VERSION 5.7 ;
  NOWIREEXTENSIONATPIN ON ;
  DIVIDERCHAR "/" ;
  BUSBITCHARS "[]" ;
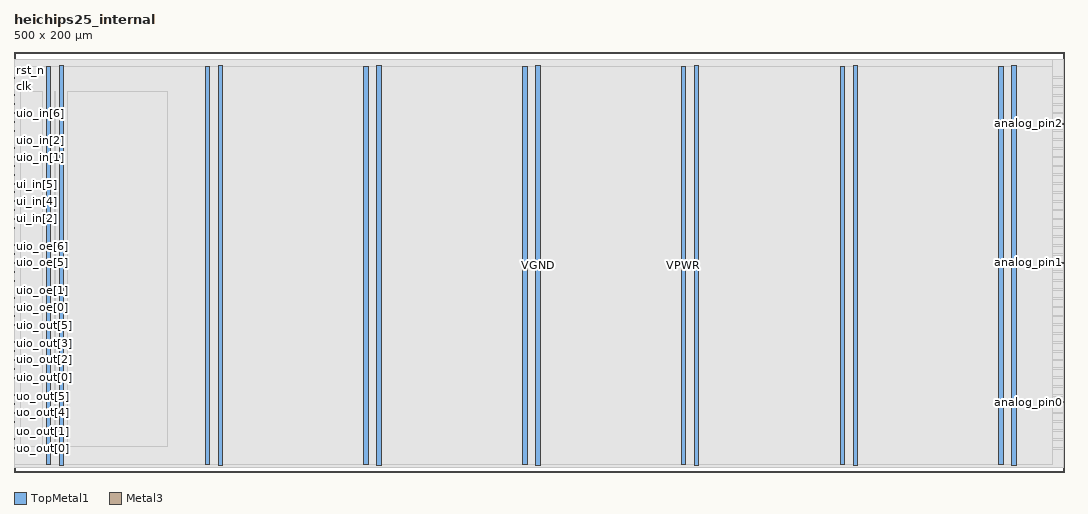
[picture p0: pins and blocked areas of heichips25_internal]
MACRO heichips25_internal
  CLASS BLOCK ;
  FOREIGN heichips25_internal ;
  ORIGIN 0.000 0.000 ;
  SIZE 500.000 BY 200.000 ;
  PIN VGND
    DIRECTION INOUT ;
    USE GROUND ;
    PORT
      LAYER TopMetal1 ;
        RECT 21.580 3.150 23.780 193.410 ;
    END
    PORT
      LAYER TopMetal1 ;
        RECT 97.180 3.150 99.380 193.410 ;
    END
    PORT
      LAYER TopMetal1 ;
        RECT 172.780 3.150 174.980 193.410 ;
    END
    PORT
      LAYER TopMetal1 ;
        RECT 248.380 3.150 250.580 193.410 ;
    END
    PORT
      LAYER TopMetal1 ;
        RECT 323.980 3.150 326.180 193.410 ;
    END
    PORT
      LAYER TopMetal1 ;
        RECT 399.580 3.150 401.780 193.410 ;
    END
    PORT
      LAYER TopMetal1 ;
        RECT 475.180 3.150 477.380 193.410 ;
    END
  END VGND
  PIN VPWR
    DIRECTION INOUT ;
    USE POWER ;
    PORT
      LAYER TopMetal1 ;
        RECT 15.380 3.560 17.580 193.000 ;
    END
    PORT
      LAYER TopMetal1 ;
        RECT 90.980 3.560 93.180 193.000 ;
    END
    PORT
      LAYER TopMetal1 ;
        RECT 166.580 3.560 168.780 193.000 ;
    END
    PORT
      LAYER TopMetal1 ;
        RECT 242.180 3.560 244.380 193.000 ;
    END
    PORT
      LAYER TopMetal1 ;
        RECT 317.780 3.560 319.980 193.000 ;
    END
    PORT
      LAYER TopMetal1 ;
        RECT 393.380 3.560 395.580 193.000 ;
    END
    PORT
      LAYER TopMetal1 ;
        RECT 468.980 3.560 471.180 193.000 ;
    END
  END VPWR
  PIN analog_pin0
    DIRECTION INOUT ;
    USE SIGNAL ;
    ANTENNADIFFAREA 5.654400 ;
    PORT
      LAYER Metal3 ;
        RECT 490.660 32.980 500.000 33.380 ;
    END
  END analog_pin0
  PIN analog_pin1
    DIRECTION INOUT ;
    USE SIGNAL ;
    ANTENNADIFFAREA 5.654400 ;
    PORT
      LAYER Metal3 ;
        RECT 494.980 99.340 500.000 99.740 ;
    END
  END analog_pin1
  PIN analog_pin2
    DIRECTION INOUT ;
    USE SIGNAL ;
    ANTENNADIFFAREA 5.654400 ;
    PORT
      LAYER Metal3 ;
        RECT 495.460 165.700 500.000 166.100 ;
    END
  END analog_pin2
  PIN clk
    DIRECTION INPUT ;
    USE SIGNAL ;
    ANTENNAGATEAREA 2.901600 ;
    PORT
      LAYER Metal3 ;
        RECT 0.000 183.340 0.400 183.740 ;
    END
  END clk
  PIN ena
    DIRECTION INPUT ;
    USE SIGNAL ;
    ANTENNAGATEAREA 0.180700 ;
    ANTENNADIFFAREA 2.015400 ;
    PORT
      LAYER Metal3 ;
        RECT 0.000 179.140 0.400 179.540 ;
    END
  END ena
  PIN rst_n
    DIRECTION INPUT ;
    USE SIGNAL ;
    ANTENNAGATEAREA 0.180700 ;
    PORT
      LAYER Metal3 ;
        RECT 0.000 187.540 0.400 187.940 ;
    END
  END rst_n
  PIN ui_in[0]
    DIRECTION INPUT ;
    USE SIGNAL ;
    ANTENNAGATEAREA 0.180700 ;
    PORT
      LAYER Metal3 ;
        RECT 0.000 111.940 0.400 112.340 ;
    END
  END ui_in[0]
  PIN ui_in[1]
    DIRECTION INPUT ;
    USE SIGNAL ;
    ANTENNAGATEAREA 0.180700 ;
    PORT
      LAYER Metal3 ;
        RECT 0.000 116.140 0.400 116.540 ;
    END
  END ui_in[1]
  PIN ui_in[2]
    DIRECTION INPUT ;
    USE SIGNAL ;
    ANTENNAGATEAREA 0.180700 ;
    PORT
      LAYER Metal3 ;
        RECT 0.000 120.340 0.400 120.740 ;
    END
  END ui_in[2]
  PIN ui_in[3]
    DIRECTION INPUT ;
    USE SIGNAL ;
    ANTENNAGATEAREA 0.180700 ;
    PORT
      LAYER Metal3 ;
        RECT 0.000 124.540 0.400 124.940 ;
    END
  END ui_in[3]
  PIN ui_in[4]
    DIRECTION INPUT ;
    USE SIGNAL ;
    ANTENNAGATEAREA 0.180700 ;
    PORT
      LAYER Metal3 ;
        RECT 0.000 128.740 0.400 129.140 ;
    END
  END ui_in[4]
  PIN ui_in[5]
    DIRECTION INPUT ;
    USE SIGNAL ;
    ANTENNAGATEAREA 0.180700 ;
    ANTENNADIFFAREA 2.015400 ;
    PORT
      LAYER Metal3 ;
        RECT 0.000 132.940 0.400 133.340 ;
    END
  END ui_in[5]
  PIN ui_in[6]
    DIRECTION INPUT ;
    USE SIGNAL ;
    ANTENNAGATEAREA 0.180700 ;
    PORT
      LAYER Metal3 ;
        RECT 0.000 137.140 0.400 137.540 ;
    END
  END ui_in[6]
  PIN ui_in[7]
    DIRECTION INPUT ;
    USE SIGNAL ;
    ANTENNAGATEAREA 0.180700 ;
    PORT
      LAYER Metal3 ;
        RECT 0.000 141.340 0.400 141.740 ;
    END
  END ui_in[7]
  PIN uio_in[0]
    DIRECTION INPUT ;
    USE SIGNAL ;
    ANTENNAGATEAREA 0.180700 ;
    ANTENNADIFFAREA 2.015400 ;
    PORT
      LAYER Metal3 ;
        RECT 0.000 145.540 0.400 145.940 ;
    END
  END uio_in[0]
  PIN uio_in[1]
    DIRECTION INPUT ;
    USE SIGNAL ;
    ANTENNAGATEAREA 0.180700 ;
    PORT
      LAYER Metal3 ;
        RECT 0.000 149.740 0.400 150.140 ;
    END
  END uio_in[1]
  PIN uio_in[2]
    DIRECTION INPUT ;
    USE SIGNAL ;
    ANTENNAGATEAREA 0.180700 ;
    PORT
      LAYER Metal3 ;
        RECT 0.000 153.940 0.400 154.340 ;
    END
  END uio_in[2]
  PIN uio_in[3]
    DIRECTION INPUT ;
    USE SIGNAL ;
    ANTENNAGATEAREA 0.180700 ;
    PORT
      LAYER Metal3 ;
        RECT 0.000 158.140 0.400 158.540 ;
    END
  END uio_in[3]
  PIN uio_in[4]
    DIRECTION INPUT ;
    USE SIGNAL ;
    PORT
      LAYER Metal3 ;
        RECT 0.000 162.340 0.400 162.740 ;
    END
  END uio_in[4]
  PIN uio_in[5]
    DIRECTION INPUT ;
    USE SIGNAL ;
    PORT
      LAYER Metal3 ;
        RECT 0.000 166.540 0.400 166.940 ;
    END
  END uio_in[5]
  PIN uio_in[6]
    DIRECTION INPUT ;
    USE SIGNAL ;
    PORT
      LAYER Metal3 ;
        RECT 0.000 170.740 0.400 171.140 ;
    END
  END uio_in[6]
  PIN uio_in[7]
    DIRECTION INPUT ;
    USE SIGNAL ;
    PORT
      LAYER Metal3 ;
        RECT 0.000 174.940 0.400 175.340 ;
    END
  END uio_in[7]
  PIN uio_oe[0]
    DIRECTION OUTPUT ;
    USE SIGNAL ;
    ANTENNADIFFAREA 0.708600 ;
    PORT
      LAYER Metal3 ;
        RECT 0.000 78.340 0.400 78.740 ;
    END
  END uio_oe[0]
  PIN uio_oe[1]
    DIRECTION OUTPUT ;
    USE SIGNAL ;
    ANTENNADIFFAREA 0.708600 ;
    PORT
      LAYER Metal3 ;
        RECT 0.000 82.540 0.400 82.940 ;
    END
  END uio_oe[1]
  PIN uio_oe[2]
    DIRECTION OUTPUT ;
    USE SIGNAL ;
    ANTENNADIFFAREA 0.708600 ;
    PORT
      LAYER Metal3 ;
        RECT 0.000 86.740 0.400 87.140 ;
    END
  END uio_oe[2]
  PIN uio_oe[3]
    DIRECTION OUTPUT ;
    USE SIGNAL ;
    ANTENNADIFFAREA 0.708600 ;
    PORT
      LAYER Metal3 ;
        RECT 0.000 90.940 0.400 91.340 ;
    END
  END uio_oe[3]
  PIN uio_oe[4]
    DIRECTION OUTPUT ;
    USE SIGNAL ;
    ANTENNADIFFAREA 0.708600 ;
    PORT
      LAYER Metal3 ;
        RECT 0.000 95.140 0.400 95.540 ;
    END
  END uio_oe[4]
  PIN uio_oe[5]
    DIRECTION OUTPUT ;
    USE SIGNAL ;
    ANTENNADIFFAREA 0.708600 ;
    PORT
      LAYER Metal3 ;
        RECT 0.000 99.340 0.400 99.740 ;
    END
  END uio_oe[5]
  PIN uio_oe[6]
    DIRECTION OUTPUT ;
    USE SIGNAL ;
    ANTENNADIFFAREA 0.708600 ;
    PORT
      LAYER Metal3 ;
        RECT 0.000 103.540 0.400 103.940 ;
    END
  END uio_oe[6]
  PIN uio_oe[7]
    DIRECTION OUTPUT ;
    USE SIGNAL ;
    ANTENNADIFFAREA 0.708600 ;
    PORT
      LAYER Metal3 ;
        RECT 0.000 107.740 0.400 108.140 ;
    END
  END uio_oe[7]
  PIN uio_out[0]
    DIRECTION OUTPUT ;
    USE SIGNAL ;
    ANTENNADIFFAREA 0.708600 ;
    PORT
      LAYER Metal3 ;
        RECT 0.000 44.740 0.400 45.140 ;
    END
  END uio_out[0]
  PIN uio_out[1]
    DIRECTION OUTPUT ;
    USE SIGNAL ;
    ANTENNADIFFAREA 0.708600 ;
    PORT
      LAYER Metal3 ;
        RECT 0.000 48.940 0.400 49.340 ;
    END
  END uio_out[1]
  PIN uio_out[2]
    DIRECTION OUTPUT ;
    USE SIGNAL ;
    ANTENNADIFFAREA 0.708600 ;
    PORT
      LAYER Metal3 ;
        RECT 0.000 53.140 0.400 53.540 ;
    END
  END uio_out[2]
  PIN uio_out[3]
    DIRECTION OUTPUT ;
    USE SIGNAL ;
    ANTENNADIFFAREA 0.708600 ;
    PORT
      LAYER Metal3 ;
        RECT 0.000 57.340 0.400 57.740 ;
    END
  END uio_out[3]
  PIN uio_out[4]
    DIRECTION OUTPUT ;
    USE SIGNAL ;
    ANTENNADIFFAREA 0.708600 ;
    PORT
      LAYER Metal3 ;
        RECT 0.000 61.540 0.400 61.940 ;
    END
  END uio_out[4]
  PIN uio_out[5]
    DIRECTION OUTPUT ;
    USE SIGNAL ;
    ANTENNADIFFAREA 0.708600 ;
    PORT
      LAYER Metal3 ;
        RECT 0.000 65.740 0.400 66.140 ;
    END
  END uio_out[5]
  PIN uio_out[6]
    DIRECTION OUTPUT ;
    USE SIGNAL ;
    ANTENNADIFFAREA 0.708600 ;
    PORT
      LAYER Metal3 ;
        RECT 0.000 69.940 0.400 70.340 ;
    END
  END uio_out[6]
  PIN uio_out[7]
    DIRECTION OUTPUT ;
    USE SIGNAL ;
    ANTENNADIFFAREA 0.708600 ;
    PORT
      LAYER Metal3 ;
        RECT 0.000 74.140 0.400 74.540 ;
    END
  END uio_out[7]
  PIN uo_out[0]
    DIRECTION OUTPUT ;
    USE SIGNAL ;
    ANTENNADIFFAREA 0.708600 ;
    PORT
      LAYER Metal3 ;
        RECT 0.000 11.140 0.400 11.540 ;
    END
  END uo_out[0]
  PIN uo_out[1]
    DIRECTION OUTPUT ;
    USE SIGNAL ;
    ANTENNADIFFAREA 0.708600 ;
    PORT
      LAYER Metal3 ;
        RECT 0.000 15.340 0.400 15.740 ;
    END
  END uo_out[1]
  PIN uo_out[2]
    DIRECTION OUTPUT ;
    USE SIGNAL ;
    ANTENNADIFFAREA 0.708600 ;
    PORT
      LAYER Metal3 ;
        RECT 0.000 19.540 0.400 19.940 ;
    END
  END uo_out[2]
  PIN uo_out[3]
    DIRECTION OUTPUT ;
    USE SIGNAL ;
    ANTENNADIFFAREA 0.708600 ;
    PORT
      LAYER Metal3 ;
        RECT 0.000 23.740 0.400 24.140 ;
    END
  END uo_out[3]
  PIN uo_out[4]
    DIRECTION OUTPUT ;
    USE SIGNAL ;
    ANTENNADIFFAREA 0.708600 ;
    PORT
      LAYER Metal3 ;
        RECT 0.000 27.940 0.400 28.340 ;
    END
  END uo_out[4]
  PIN uo_out[5]
    DIRECTION OUTPUT ;
    USE SIGNAL ;
    ANTENNADIFFAREA 0.708600 ;
    PORT
      LAYER Metal3 ;
        RECT 0.000 32.140 0.400 32.540 ;
    END
  END uo_out[5]
  PIN uo_out[6]
    DIRECTION OUTPUT ;
    USE SIGNAL ;
    ANTENNADIFFAREA 0.708600 ;
    PORT
      LAYER Metal3 ;
        RECT 0.000 36.340 0.400 36.740 ;
    END
  END uo_out[6]
  PIN uo_out[7]
    DIRECTION OUTPUT ;
    USE SIGNAL ;
    ANTENNADIFFAREA 0.708600 ;
    PORT
      LAYER Metal3 ;
        RECT 0.000 40.540 0.400 40.940 ;
    END
  END uo_out[7]
  OBS
      LAYER GatPoly ;
        RECT 2.880 3.630 496.800 192.930 ;
      LAYER Metal1 ;
        RECT 2.880 3.560 496.800 193.000 ;
      LAYER Metal2 ;
        RECT 0.375 1.955 495.660 196.285 ;
      LAYER Metal3 ;
        RECT 0.100 188.150 499.800 196.245 ;
        RECT 0.610 187.330 499.800 188.150 ;
        RECT 0.100 183.950 499.800 187.330 ;
        RECT 0.610 183.130 499.800 183.950 ;
        RECT 0.100 179.750 499.800 183.130 ;
        RECT 0.610 178.930 499.800 179.750 ;
        RECT 0.100 175.550 499.800 178.930 ;
        RECT 0.610 174.730 499.800 175.550 ;
        RECT 0.100 171.350 499.800 174.730 ;
        RECT 0.610 170.530 499.800 171.350 ;
        RECT 0.100 167.150 499.800 170.530 ;
        RECT 0.610 166.330 499.800 167.150 ;
        RECT 0.100 166.310 499.800 166.330 ;
        RECT 0.100 165.490 495.250 166.310 ;
        RECT 0.100 162.950 499.800 165.490 ;
        RECT 0.610 162.130 499.800 162.950 ;
        RECT 0.100 158.750 499.800 162.130 ;
        RECT 0.610 157.930 499.800 158.750 ;
        RECT 0.100 154.550 499.800 157.930 ;
        RECT 0.610 153.730 499.800 154.550 ;
        RECT 0.100 150.350 499.800 153.730 ;
        RECT 0.610 149.530 499.800 150.350 ;
        RECT 0.100 146.150 499.800 149.530 ;
        RECT 0.610 145.330 499.800 146.150 ;
        RECT 0.100 141.950 499.800 145.330 ;
        RECT 0.610 141.130 499.800 141.950 ;
        RECT 0.100 137.750 499.800 141.130 ;
        RECT 0.610 136.930 499.800 137.750 ;
        RECT 0.100 133.550 499.800 136.930 ;
        RECT 0.610 132.730 499.800 133.550 ;
        RECT 0.100 129.350 499.800 132.730 ;
        RECT 0.610 128.530 499.800 129.350 ;
        RECT 0.100 125.150 499.800 128.530 ;
        RECT 0.610 124.330 499.800 125.150 ;
        RECT 0.100 120.950 499.800 124.330 ;
        RECT 0.610 120.130 499.800 120.950 ;
        RECT 0.100 116.750 499.800 120.130 ;
        RECT 0.610 115.930 499.800 116.750 ;
        RECT 0.100 112.550 499.800 115.930 ;
        RECT 0.610 111.730 499.800 112.550 ;
        RECT 0.100 108.350 499.800 111.730 ;
        RECT 0.610 107.530 499.800 108.350 ;
        RECT 0.100 104.150 499.800 107.530 ;
        RECT 0.610 103.330 499.800 104.150 ;
        RECT 0.100 99.950 499.800 103.330 ;
        RECT 0.610 99.130 494.770 99.950 ;
        RECT 0.100 95.750 499.800 99.130 ;
        RECT 0.610 94.930 499.800 95.750 ;
        RECT 0.100 91.550 499.800 94.930 ;
        RECT 0.610 90.730 499.800 91.550 ;
        RECT 0.100 87.350 499.800 90.730 ;
        RECT 0.610 86.530 499.800 87.350 ;
        RECT 0.100 83.150 499.800 86.530 ;
        RECT 0.610 82.330 499.800 83.150 ;
        RECT 0.100 78.950 499.800 82.330 ;
        RECT 0.610 78.130 499.800 78.950 ;
        RECT 0.100 74.750 499.800 78.130 ;
        RECT 0.610 73.930 499.800 74.750 ;
        RECT 0.100 70.550 499.800 73.930 ;
        RECT 0.610 69.730 499.800 70.550 ;
        RECT 0.100 66.350 499.800 69.730 ;
        RECT 0.610 65.530 499.800 66.350 ;
        RECT 0.100 62.150 499.800 65.530 ;
        RECT 0.610 61.330 499.800 62.150 ;
        RECT 0.100 57.950 499.800 61.330 ;
        RECT 0.610 57.130 499.800 57.950 ;
        RECT 0.100 53.750 499.800 57.130 ;
        RECT 0.610 52.930 499.800 53.750 ;
        RECT 0.100 49.550 499.800 52.930 ;
        RECT 0.610 48.730 499.800 49.550 ;
        RECT 0.100 45.350 499.800 48.730 ;
        RECT 0.610 44.530 499.800 45.350 ;
        RECT 0.100 41.150 499.800 44.530 ;
        RECT 0.610 40.330 499.800 41.150 ;
        RECT 0.100 36.950 499.800 40.330 ;
        RECT 0.610 36.130 499.800 36.950 ;
        RECT 0.100 33.590 499.800 36.130 ;
        RECT 0.100 32.770 490.450 33.590 ;
        RECT 0.100 32.750 499.800 32.770 ;
        RECT 0.610 31.930 499.800 32.750 ;
        RECT 0.100 28.550 499.800 31.930 ;
        RECT 0.610 27.730 499.800 28.550 ;
        RECT 0.100 24.350 499.800 27.730 ;
        RECT 0.610 23.530 499.800 24.350 ;
        RECT 0.100 20.150 499.800 23.530 ;
        RECT 0.610 19.330 499.800 20.150 ;
        RECT 0.100 15.950 499.800 19.330 ;
        RECT 0.610 15.130 499.800 15.950 ;
        RECT 0.100 11.750 499.800 15.130 ;
        RECT 0.610 10.930 499.800 11.750 ;
        RECT 0.100 2.000 499.800 10.930 ;
      LAYER Metal4 ;
        RECT 0.375 3.635 494.505 196.285 ;
      LAYER Metal5 ;
        RECT 0.335 3.470 494.545 193.090 ;
      LAYER TopMetal1 ;
        RECT 3.100 12.200 13.740 181.000 ;
        RECT 19.220 12.200 19.940 181.000 ;
        RECT 25.420 12.200 73.140 181.000 ;
  END
END heichips25_internal
END LIBRARY

